VERSION 5.7 ;
  NOWIREEXTENSIONATPIN ON ;
  DIVIDERCHAR "/" ;
  BUSBITCHARS "[]" ;
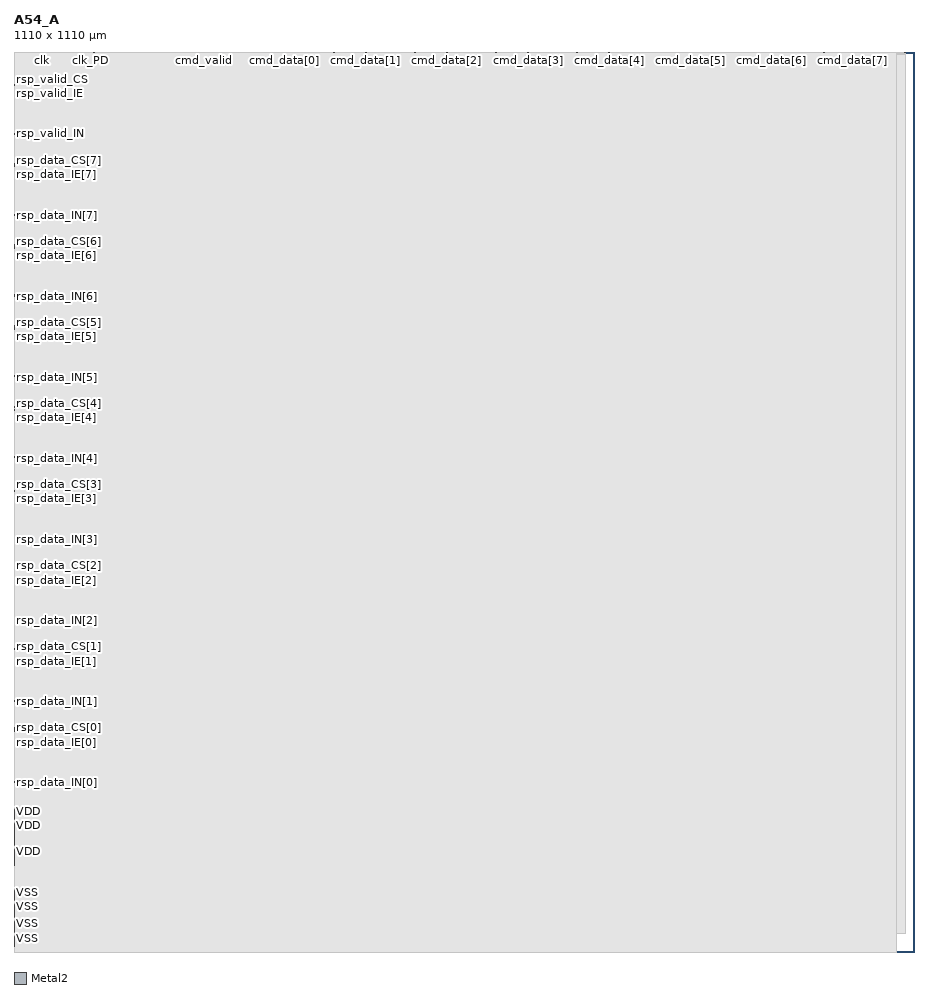
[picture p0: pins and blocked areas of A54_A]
MACRO A54_A
  CLASS BLOCK ;
  FOREIGN A54_A ;
  ORIGIN 0.000 0.000 ;
  SIZE 1110.000 BY 1110.000 ;
  PIN VDD
    DIRECTION INOUT ;
    USE POWER ;
    PORT
      LAYER Metal2 ;
        RECT 0.000 106.360 1.000 178.640 ;
    END
  END VDD
  PIN VDD
    DIRECTION INOUT ;
    USE POWER ;
    PORT
      LAYER Metal2 ;
        RECT 0.000 118.760 1.000 129.010 ;
    END
  END VDD
  PIN VDD
    DIRECTION INOUT ;
    USE POWER ;
    PORT
      LAYER Metal2 ;
        RECT 0.000 130.610 1.000 140.860 ;
    END
  END VDD
  PIN VDD
    DIRECTION INOUT ;
    USE POWER ;
    PORT
      LAYER Metal2 ;
        RECT 0.000 144.140 1.000 154.390 ;
    END
  END VDD
  PIN VDD
    DIRECTION INOUT ;
    USE POWER ;
    PORT
      LAYER Metal2 ;
        RECT 0.000 155.990 1.000 166.240 ;
    END
  END VDD
  PIN VDD
    DIRECTION INOUT ;
    USE POWER ;
    PORT
      LAYER Metal2 ;
        RECT 0.000 169.140 1.000 178.640 ;
    END
  END VDD
  PIN VSS
    DIRECTION INOUT ;
    USE GROUND ;
    PORT
      LAYER Metal2 ;
        RECT 0.000 6.360 1.000 78.640 ;
    END
  END VSS
  PIN VSS
    DIRECTION INOUT ;
    USE GROUND ;
    PORT
      LAYER Metal2 ;
        RECT 0.000 18.760 1.000 29.010 ;
    END
  END VSS
  PIN VSS
    DIRECTION INOUT ;
    USE GROUND ;
    PORT
      LAYER Metal2 ;
        RECT 0.000 30.610 1.000 40.860 ;
    END
  END VSS
  PIN VSS
    DIRECTION INOUT ;
    USE GROUND ;
    PORT
      LAYER Metal2 ;
        RECT 0.000 44.140 1.000 54.390 ;
    END
  END VSS
  PIN VSS
    DIRECTION INOUT ;
    USE GROUND ;
    PORT
      LAYER Metal2 ;
        RECT 0.000 55.990 1.000 66.240 ;
    END
  END VSS
  PIN VSS
    DIRECTION INOUT ;
    USE GROUND ;
    PORT
      LAYER Metal2 ;
        RECT 0.000 69.140 1.000 78.640 ;
    END
  END VSS
  PIN clk
    DIRECTION INPUT ;
    USE SIGNAL ;
    ANTENNAGATEAREA 4.738000 ;
    ANTENNADIFFAREA 0.410400 ;
    PORT
      LAYER Metal2 ;
        RECT 33.760 1109.000 34.140 1110.000 ;
    END
  END clk
  PIN clk_PD
    DIRECTION OUTPUT ;
    USE SIGNAL ;
    ANTENNADIFFAREA 0.360800 ;
    PORT
      LAYER Metal2 ;
        RECT 94.290 1109.000 94.670 1110.000 ;
    END
  END clk_PD
  PIN clk_PU
    DIRECTION OUTPUT ;
    USE SIGNAL ;
    ANTENNADIFFAREA 0.360800 ;
    PORT
      LAYER Metal2 ;
        RECT 98.655 1109.000 99.035 1110.000 ;
    END
  END clk_PU
  PIN cmd_data[0]
    DIRECTION INPUT ;
    USE SIGNAL ;
    ANTENNAGATEAREA 1.102000 ;
    ANTENNADIFFAREA 0.410400 ;
    PORT
      LAYER Metal2 ;
        RECT 333.760 1109.000 334.140 1110.000 ;
    END
  END cmd_data[0]
  PIN cmd_data[1]
    DIRECTION INPUT ;
    USE SIGNAL ;
    ANTENNAGATEAREA 1.102000 ;
    ANTENNADIFFAREA 0.410400 ;
    PORT
      LAYER Metal2 ;
        RECT 433.760 1109.000 434.140 1110.000 ;
    END
  END cmd_data[1]
  PIN cmd_data[2]
    DIRECTION INPUT ;
    USE SIGNAL ;
    ANTENNAGATEAREA 0.396000 ;
    ANTENNADIFFAREA 0.410400 ;
    PORT
      LAYER Metal2 ;
        RECT 533.760 1109.000 534.140 1110.000 ;
    END
  END cmd_data[2]
  PIN cmd_data[3]
    DIRECTION INPUT ;
    USE SIGNAL ;
    ANTENNAGATEAREA 0.396000 ;
    ANTENNADIFFAREA 0.410400 ;
    PORT
      LAYER Metal2 ;
        RECT 633.760 1109.000 634.140 1110.000 ;
    END
  END cmd_data[3]
  PIN cmd_data[4]
    DIRECTION INPUT ;
    USE SIGNAL ;
    ANTENNAGATEAREA 0.396000 ;
    ANTENNADIFFAREA 0.410400 ;
    PORT
      LAYER Metal2 ;
        RECT 733.760 1109.000 734.140 1110.000 ;
    END
  END cmd_data[4]
  PIN cmd_data[5]
    DIRECTION INPUT ;
    USE SIGNAL ;
    ANTENNAGATEAREA 0.396000 ;
    ANTENNADIFFAREA 0.410400 ;
    PORT
      LAYER Metal2 ;
        RECT 833.760 1109.000 834.140 1110.000 ;
    END
  END cmd_data[5]
  PIN cmd_data[6]
    DIRECTION INPUT ;
    USE SIGNAL ;
    ANTENNAGATEAREA 0.396000 ;
    ANTENNADIFFAREA 0.410400 ;
    PORT
      LAYER Metal2 ;
        RECT 933.760 1109.000 934.140 1110.000 ;
    END
  END cmd_data[6]
  PIN cmd_data[7]
    DIRECTION INPUT ;
    USE SIGNAL ;
    ANTENNAGATEAREA 0.396000 ;
    ANTENNADIFFAREA 0.410400 ;
    PORT
      LAYER Metal2 ;
        RECT 1033.760 1109.000 1034.140 1110.000 ;
    END
  END cmd_data[7]
  PIN cmd_data_PD[0]
    DIRECTION OUTPUT ;
    USE SIGNAL ;
    ANTENNADIFFAREA 0.360800 ;
    PORT
      LAYER Metal2 ;
        RECT 394.290 1109.000 394.670 1110.000 ;
    END
  END cmd_data_PD[0]
  PIN cmd_data_PD[1]
    DIRECTION OUTPUT ;
    USE SIGNAL ;
    ANTENNADIFFAREA 0.360800 ;
    PORT
      LAYER Metal2 ;
        RECT 494.290 1109.000 494.670 1110.000 ;
    END
  END cmd_data_PD[1]
  PIN cmd_data_PD[2]
    DIRECTION OUTPUT ;
    USE SIGNAL ;
    ANTENNADIFFAREA 0.360800 ;
    PORT
      LAYER Metal2 ;
        RECT 594.290 1109.000 594.670 1110.000 ;
    END
  END cmd_data_PD[2]
  PIN cmd_data_PD[3]
    DIRECTION OUTPUT ;
    USE SIGNAL ;
    ANTENNADIFFAREA 0.360800 ;
    PORT
      LAYER Metal2 ;
        RECT 694.290 1109.000 694.670 1110.000 ;
    END
  END cmd_data_PD[3]
  PIN cmd_data_PD[4]
    DIRECTION OUTPUT ;
    USE SIGNAL ;
    ANTENNADIFFAREA 0.360800 ;
    PORT
      LAYER Metal2 ;
        RECT 794.290 1109.000 794.670 1110.000 ;
    END
  END cmd_data_PD[4]
  PIN cmd_data_PD[5]
    DIRECTION OUTPUT ;
    USE SIGNAL ;
    ANTENNADIFFAREA 0.360800 ;
    PORT
      LAYER Metal2 ;
        RECT 894.290 1109.000 894.670 1110.000 ;
    END
  END cmd_data_PD[5]
  PIN cmd_data_PD[6]
    DIRECTION OUTPUT ;
    USE SIGNAL ;
    ANTENNADIFFAREA 0.360800 ;
    PORT
      LAYER Metal2 ;
        RECT 994.290 1109.000 994.670 1110.000 ;
    END
  END cmd_data_PD[6]
  PIN cmd_data_PD[7]
    DIRECTION OUTPUT ;
    USE SIGNAL ;
    ANTENNADIFFAREA 0.360800 ;
    PORT
      LAYER Metal2 ;
        RECT 1094.290 1109.000 1094.670 1110.000 ;
    END
  END cmd_data_PD[7]
  PIN cmd_data_PU[0]
    DIRECTION OUTPUT ;
    USE SIGNAL ;
    ANTENNADIFFAREA 0.360800 ;
    PORT
      LAYER Metal2 ;
        RECT 398.655 1109.000 399.035 1110.000 ;
    END
  END cmd_data_PU[0]
  PIN cmd_data_PU[1]
    DIRECTION OUTPUT ;
    USE SIGNAL ;
    ANTENNADIFFAREA 0.360800 ;
    PORT
      LAYER Metal2 ;
        RECT 498.655 1109.000 499.035 1110.000 ;
    END
  END cmd_data_PU[1]
  PIN cmd_data_PU[2]
    DIRECTION OUTPUT ;
    USE SIGNAL ;
    ANTENNADIFFAREA 0.360800 ;
    PORT
      LAYER Metal2 ;
        RECT 598.655 1109.000 599.035 1110.000 ;
    END
  END cmd_data_PU[2]
  PIN cmd_data_PU[3]
    DIRECTION OUTPUT ;
    USE SIGNAL ;
    ANTENNADIFFAREA 0.360800 ;
    PORT
      LAYER Metal2 ;
        RECT 698.655 1109.000 699.035 1110.000 ;
    END
  END cmd_data_PU[3]
  PIN cmd_data_PU[4]
    DIRECTION OUTPUT ;
    USE SIGNAL ;
    ANTENNADIFFAREA 0.360800 ;
    PORT
      LAYER Metal2 ;
        RECT 798.655 1109.000 799.035 1110.000 ;
    END
  END cmd_data_PU[4]
  PIN cmd_data_PU[5]
    DIRECTION OUTPUT ;
    USE SIGNAL ;
    ANTENNADIFFAREA 0.360800 ;
    PORT
      LAYER Metal2 ;
        RECT 898.655 1109.000 899.035 1110.000 ;
    END
  END cmd_data_PU[5]
  PIN cmd_data_PU[6]
    DIRECTION OUTPUT ;
    USE SIGNAL ;
    ANTENNADIFFAREA 0.360800 ;
    PORT
      LAYER Metal2 ;
        RECT 998.655 1109.000 999.035 1110.000 ;
    END
  END cmd_data_PU[6]
  PIN cmd_data_PU[7]
    DIRECTION OUTPUT ;
    USE SIGNAL ;
    ANTENNADIFFAREA 0.360800 ;
    PORT
      LAYER Metal2 ;
        RECT 1098.655 1109.000 1099.035 1110.000 ;
    END
  END cmd_data_PU[7]
  PIN cmd_valid
    DIRECTION INPUT ;
    USE SIGNAL ;
    ANTENNAGATEAREA 0.396000 ;
    ANTENNADIFFAREA 0.410400 ;
    PORT
      LAYER Metal2 ;
        RECT 233.760 1109.000 234.140 1110.000 ;
    END
  END cmd_valid
  PIN cmd_valid_PD
    DIRECTION OUTPUT ;
    USE SIGNAL ;
    ANTENNADIFFAREA 0.360800 ;
    PORT
      LAYER Metal2 ;
        RECT 294.290 1109.000 294.670 1110.000 ;
    END
  END cmd_valid_PD
  PIN cmd_valid_PU
    DIRECTION OUTPUT ;
    USE SIGNAL ;
    ANTENNADIFFAREA 0.360800 ;
    PORT
      LAYER Metal2 ;
        RECT 298.655 1109.000 299.035 1110.000 ;
    END
  END cmd_valid_PU
  PIN rsp_data_CS[0]
    DIRECTION OUTPUT ;
    USE SIGNAL ;
    ANTENNADIFFAREA 0.360800 ;
    PORT
      LAYER Metal2 ;
        RECT 0.000 276.260 1.000 276.640 ;
    END
  END rsp_data_CS[0]
  PIN rsp_data_CS[1]
    DIRECTION OUTPUT ;
    USE SIGNAL ;
    ANTENNADIFFAREA 0.360800 ;
    PORT
      LAYER Metal2 ;
        RECT 0.000 376.260 1.000 376.640 ;
    END
  END rsp_data_CS[1]
  PIN rsp_data_CS[2]
    DIRECTION OUTPUT ;
    USE SIGNAL ;
    ANTENNADIFFAREA 0.360800 ;
    PORT
      LAYER Metal2 ;
        RECT 0.000 476.260 1.000 476.640 ;
    END
  END rsp_data_CS[2]
  PIN rsp_data_CS[3]
    DIRECTION OUTPUT ;
    USE SIGNAL ;
    ANTENNADIFFAREA 0.360800 ;
    PORT
      LAYER Metal2 ;
        RECT 0.000 576.260 1.000 576.640 ;
    END
  END rsp_data_CS[3]
  PIN rsp_data_CS[4]
    DIRECTION OUTPUT ;
    USE SIGNAL ;
    ANTENNADIFFAREA 0.360800 ;
    PORT
      LAYER Metal2 ;
        RECT 0.000 676.260 1.000 676.640 ;
    END
  END rsp_data_CS[4]
  PIN rsp_data_CS[5]
    DIRECTION OUTPUT ;
    USE SIGNAL ;
    ANTENNADIFFAREA 0.360800 ;
    PORT
      LAYER Metal2 ;
        RECT 0.000 776.260 1.000 776.640 ;
    END
  END rsp_data_CS[5]
  PIN rsp_data_CS[6]
    DIRECTION OUTPUT ;
    USE SIGNAL ;
    ANTENNADIFFAREA 0.360800 ;
    PORT
      LAYER Metal2 ;
        RECT 0.000 876.260 1.000 876.640 ;
    END
  END rsp_data_CS[6]
  PIN rsp_data_CS[7]
    DIRECTION OUTPUT ;
    USE SIGNAL ;
    ANTENNADIFFAREA 0.360800 ;
    PORT
      LAYER Metal2 ;
        RECT 0.000 976.260 1.000 976.640 ;
    END
  END rsp_data_CS[7]
  PIN rsp_data_IE[0]
    DIRECTION OUTPUT ;
    USE SIGNAL ;
    ANTENNADIFFAREA 0.360800 ;
    PORT
      LAYER Metal2 ;
        RECT 0.000 268.235 1.000 268.615 ;
    END
  END rsp_data_IE[0]
  PIN rsp_data_IE[1]
    DIRECTION OUTPUT ;
    USE SIGNAL ;
    ANTENNADIFFAREA 0.360800 ;
    PORT
      LAYER Metal2 ;
        RECT 0.000 368.235 1.000 368.615 ;
    END
  END rsp_data_IE[1]
  PIN rsp_data_IE[2]
    DIRECTION OUTPUT ;
    USE SIGNAL ;
    ANTENNADIFFAREA 0.360800 ;
    PORT
      LAYER Metal2 ;
        RECT 0.000 468.235 1.000 468.615 ;
    END
  END rsp_data_IE[2]
  PIN rsp_data_IE[3]
    DIRECTION OUTPUT ;
    USE SIGNAL ;
    ANTENNADIFFAREA 0.360800 ;
    PORT
      LAYER Metal2 ;
        RECT 0.000 568.235 1.000 568.615 ;
    END
  END rsp_data_IE[3]
  PIN rsp_data_IE[4]
    DIRECTION OUTPUT ;
    USE SIGNAL ;
    ANTENNADIFFAREA 0.360800 ;
    PORT
      LAYER Metal2 ;
        RECT 0.000 668.235 1.000 668.615 ;
    END
  END rsp_data_IE[4]
  PIN rsp_data_IE[5]
    DIRECTION OUTPUT ;
    USE SIGNAL ;
    ANTENNADIFFAREA 0.360800 ;
    PORT
      LAYER Metal2 ;
        RECT 0.000 768.235 1.000 768.615 ;
    END
  END rsp_data_IE[5]
  PIN rsp_data_IE[6]
    DIRECTION OUTPUT ;
    USE SIGNAL ;
    ANTENNADIFFAREA 0.360800 ;
    PORT
      LAYER Metal2 ;
        RECT 0.000 868.235 1.000 868.615 ;
    END
  END rsp_data_IE[6]
  PIN rsp_data_IE[7]
    DIRECTION OUTPUT ;
    USE SIGNAL ;
    ANTENNADIFFAREA 0.360800 ;
    PORT
      LAYER Metal2 ;
        RECT 0.000 968.235 1.000 968.615 ;
    END
  END rsp_data_IE[7]
  PIN rsp_data_IN[0]
    DIRECTION INPUT ;
    USE SIGNAL ;
    PORT
      LAYER Metal2 ;
        RECT 0.000 208.760 1.000 209.140 ;
    END
  END rsp_data_IN[0]
  PIN rsp_data_IN[1]
    DIRECTION INPUT ;
    USE SIGNAL ;
    PORT
      LAYER Metal2 ;
        RECT 0.000 308.760 1.000 309.140 ;
    END
  END rsp_data_IN[1]
  PIN rsp_data_IN[2]
    DIRECTION INPUT ;
    USE SIGNAL ;
    PORT
      LAYER Metal2 ;
        RECT 0.000 408.760 1.000 409.140 ;
    END
  END rsp_data_IN[2]
  PIN rsp_data_IN[3]
    DIRECTION INPUT ;
    USE SIGNAL ;
    PORT
      LAYER Metal2 ;
        RECT 0.000 508.760 1.000 509.140 ;
    END
  END rsp_data_IN[3]
  PIN rsp_data_IN[4]
    DIRECTION INPUT ;
    USE SIGNAL ;
    PORT
      LAYER Metal2 ;
        RECT 0.000 608.760 1.000 609.140 ;
    END
  END rsp_data_IN[4]
  PIN rsp_data_IN[5]
    DIRECTION INPUT ;
    USE SIGNAL ;
    PORT
      LAYER Metal2 ;
        RECT 0.000 708.760 1.000 709.140 ;
    END
  END rsp_data_IN[5]
  PIN rsp_data_IN[6]
    DIRECTION INPUT ;
    USE SIGNAL ;
    PORT
      LAYER Metal2 ;
        RECT 0.000 808.760 1.000 809.140 ;
    END
  END rsp_data_IN[6]
  PIN rsp_data_IN[7]
    DIRECTION INPUT ;
    USE SIGNAL ;
    PORT
      LAYER Metal2 ;
        RECT 0.000 908.760 1.000 909.140 ;
    END
  END rsp_data_IN[7]
  PIN rsp_data_OE[0]
    DIRECTION OUTPUT ;
    USE SIGNAL ;
    ANTENNADIFFAREA 0.536800 ;
    PORT
      LAYER Metal2 ;
        RECT 0.000 209.490 1.000 209.870 ;
    END
  END rsp_data_OE[0]
  PIN rsp_data_OE[1]
    DIRECTION OUTPUT ;
    USE SIGNAL ;
    ANTENNADIFFAREA 0.536800 ;
    PORT
      LAYER Metal2 ;
        RECT 0.000 309.490 1.000 309.870 ;
    END
  END rsp_data_OE[1]
  PIN rsp_data_OE[2]
    DIRECTION OUTPUT ;
    USE SIGNAL ;
    ANTENNADIFFAREA 0.536800 ;
    PORT
      LAYER Metal2 ;
        RECT 0.000 409.490 1.000 409.870 ;
    END
  END rsp_data_OE[2]
  PIN rsp_data_OE[3]
    DIRECTION OUTPUT ;
    USE SIGNAL ;
    ANTENNADIFFAREA 0.536800 ;
    PORT
      LAYER Metal2 ;
        RECT 0.000 509.490 1.000 509.870 ;
    END
  END rsp_data_OE[3]
  PIN rsp_data_OE[4]
    DIRECTION OUTPUT ;
    USE SIGNAL ;
    ANTENNADIFFAREA 0.536800 ;
    PORT
      LAYER Metal2 ;
        RECT 0.000 609.490 1.000 609.870 ;
    END
  END rsp_data_OE[4]
  PIN rsp_data_OE[5]
    DIRECTION OUTPUT ;
    USE SIGNAL ;
    ANTENNADIFFAREA 0.536800 ;
    PORT
      LAYER Metal2 ;
        RECT 0.000 709.490 1.000 709.870 ;
    END
  END rsp_data_OE[5]
  PIN rsp_data_OE[6]
    DIRECTION OUTPUT ;
    USE SIGNAL ;
    ANTENNADIFFAREA 0.536800 ;
    PORT
      LAYER Metal2 ;
        RECT 0.000 809.490 1.000 809.870 ;
    END
  END rsp_data_OE[6]
  PIN rsp_data_OE[7]
    DIRECTION OUTPUT ;
    USE SIGNAL ;
    ANTENNADIFFAREA 0.536800 ;
    PORT
      LAYER Metal2 ;
        RECT 0.000 909.490 1.000 909.870 ;
    END
  END rsp_data_OE[7]
  PIN rsp_data_OUT[0]
    DIRECTION OUTPUT ;
    USE SIGNAL ;
    ANTENNADIFFAREA 0.897600 ;
    PORT
      LAYER Metal2 ;
        RECT 0.000 210.220 1.000 210.600 ;
    END
  END rsp_data_OUT[0]
  PIN rsp_data_OUT[1]
    DIRECTION OUTPUT ;
    USE SIGNAL ;
    ANTENNADIFFAREA 0.897600 ;
    PORT
      LAYER Metal2 ;
        RECT 0.000 310.220 1.000 310.600 ;
    END
  END rsp_data_OUT[1]
  PIN rsp_data_OUT[2]
    DIRECTION OUTPUT ;
    USE SIGNAL ;
    ANTENNADIFFAREA 0.897600 ;
    PORT
      LAYER Metal2 ;
        RECT 0.000 410.220 1.000 410.600 ;
    END
  END rsp_data_OUT[2]
  PIN rsp_data_OUT[3]
    DIRECTION OUTPUT ;
    USE SIGNAL ;
    ANTENNADIFFAREA 0.897600 ;
    PORT
      LAYER Metal2 ;
        RECT 0.000 510.220 1.000 510.600 ;
    END
  END rsp_data_OUT[3]
  PIN rsp_data_OUT[4]
    DIRECTION OUTPUT ;
    USE SIGNAL ;
    ANTENNADIFFAREA 0.897600 ;
    PORT
      LAYER Metal2 ;
        RECT 0.000 610.220 1.000 610.600 ;
    END
  END rsp_data_OUT[4]
  PIN rsp_data_OUT[5]
    DIRECTION OUTPUT ;
    USE SIGNAL ;
    ANTENNADIFFAREA 0.897600 ;
    PORT
      LAYER Metal2 ;
        RECT 0.000 710.220 1.000 710.600 ;
    END
  END rsp_data_OUT[5]
  PIN rsp_data_OUT[6]
    DIRECTION OUTPUT ;
    USE SIGNAL ;
    ANTENNADIFFAREA 0.897600 ;
    PORT
      LAYER Metal2 ;
        RECT 0.000 810.220 1.000 810.600 ;
    END
  END rsp_data_OUT[6]
  PIN rsp_data_OUT[7]
    DIRECTION OUTPUT ;
    USE SIGNAL ;
    ANTENNADIFFAREA 0.897600 ;
    PORT
      LAYER Metal2 ;
        RECT 0.000 910.220 1.000 910.600 ;
    END
  END rsp_data_OUT[7]
  PIN rsp_data_PDRV0[0]
    DIRECTION OUTPUT ;
    USE SIGNAL ;
    ANTENNADIFFAREA 0.360800 ;
    PORT
      LAYER Metal2 ;
        RECT 0.000 272.510 1.000 272.890 ;
    END
  END rsp_data_PDRV0[0]
  PIN rsp_data_PDRV0[1]
    DIRECTION OUTPUT ;
    USE SIGNAL ;
    ANTENNADIFFAREA 0.360800 ;
    PORT
      LAYER Metal2 ;
        RECT 0.000 372.510 1.000 372.890 ;
    END
  END rsp_data_PDRV0[1]
  PIN rsp_data_PDRV0[2]
    DIRECTION OUTPUT ;
    USE SIGNAL ;
    ANTENNADIFFAREA 0.360800 ;
    PORT
      LAYER Metal2 ;
        RECT 0.000 472.510 1.000 472.890 ;
    END
  END rsp_data_PDRV0[2]
  PIN rsp_data_PDRV0[3]
    DIRECTION OUTPUT ;
    USE SIGNAL ;
    ANTENNADIFFAREA 0.360800 ;
    PORT
      LAYER Metal2 ;
        RECT 0.000 572.510 1.000 572.890 ;
    END
  END rsp_data_PDRV0[3]
  PIN rsp_data_PDRV0[4]
    DIRECTION OUTPUT ;
    USE SIGNAL ;
    ANTENNADIFFAREA 0.360800 ;
    PORT
      LAYER Metal2 ;
        RECT 0.000 672.510 1.000 672.890 ;
    END
  END rsp_data_PDRV0[4]
  PIN rsp_data_PDRV0[5]
    DIRECTION OUTPUT ;
    USE SIGNAL ;
    ANTENNADIFFAREA 0.360800 ;
    PORT
      LAYER Metal2 ;
        RECT 0.000 772.510 1.000 772.890 ;
    END
  END rsp_data_PDRV0[5]
  PIN rsp_data_PDRV0[6]
    DIRECTION OUTPUT ;
    USE SIGNAL ;
    ANTENNADIFFAREA 0.360800 ;
    PORT
      LAYER Metal2 ;
        RECT 0.000 872.510 1.000 872.890 ;
    END
  END rsp_data_PDRV0[6]
  PIN rsp_data_PDRV0[7]
    DIRECTION OUTPUT ;
    USE SIGNAL ;
    ANTENNADIFFAREA 0.360800 ;
    PORT
      LAYER Metal2 ;
        RECT 0.000 972.510 1.000 972.890 ;
    END
  END rsp_data_PDRV0[7]
  PIN rsp_data_PDRV1[0]
    DIRECTION OUTPUT ;
    USE SIGNAL ;
    ANTENNADIFFAREA 0.360800 ;
    PORT
      LAYER Metal2 ;
        RECT 0.000 271.800 1.000 272.180 ;
    END
  END rsp_data_PDRV1[0]
  PIN rsp_data_PDRV1[1]
    DIRECTION OUTPUT ;
    USE SIGNAL ;
    ANTENNADIFFAREA 0.360800 ;
    PORT
      LAYER Metal2 ;
        RECT 0.000 371.800 1.000 372.180 ;
    END
  END rsp_data_PDRV1[1]
  PIN rsp_data_PDRV1[2]
    DIRECTION OUTPUT ;
    USE SIGNAL ;
    ANTENNADIFFAREA 0.360800 ;
    PORT
      LAYER Metal2 ;
        RECT 0.000 471.800 1.000 472.180 ;
    END
  END rsp_data_PDRV1[2]
  PIN rsp_data_PDRV1[3]
    DIRECTION OUTPUT ;
    USE SIGNAL ;
    ANTENNADIFFAREA 0.360800 ;
    PORT
      LAYER Metal2 ;
        RECT 0.000 571.800 1.000 572.180 ;
    END
  END rsp_data_PDRV1[3]
  PIN rsp_data_PDRV1[4]
    DIRECTION OUTPUT ;
    USE SIGNAL ;
    ANTENNADIFFAREA 0.360800 ;
    PORT
      LAYER Metal2 ;
        RECT 0.000 671.800 1.000 672.180 ;
    END
  END rsp_data_PDRV1[4]
  PIN rsp_data_PDRV1[5]
    DIRECTION OUTPUT ;
    USE SIGNAL ;
    ANTENNADIFFAREA 0.360800 ;
    PORT
      LAYER Metal2 ;
        RECT 0.000 771.800 1.000 772.180 ;
    END
  END rsp_data_PDRV1[5]
  PIN rsp_data_PDRV1[6]
    DIRECTION OUTPUT ;
    USE SIGNAL ;
    ANTENNADIFFAREA 0.360800 ;
    PORT
      LAYER Metal2 ;
        RECT 0.000 871.800 1.000 872.180 ;
    END
  END rsp_data_PDRV1[6]
  PIN rsp_data_PDRV1[7]
    DIRECTION OUTPUT ;
    USE SIGNAL ;
    ANTENNADIFFAREA 0.360800 ;
    PORT
      LAYER Metal2 ;
        RECT 0.000 971.800 1.000 972.180 ;
    END
  END rsp_data_PDRV1[7]
  PIN rsp_data_PD[0]
    DIRECTION OUTPUT ;
    USE SIGNAL ;
    ANTENNADIFFAREA 0.360800 ;
    PORT
      LAYER Metal2 ;
        RECT 0.000 269.290 1.000 269.670 ;
    END
  END rsp_data_PD[0]
  PIN rsp_data_PD[1]
    DIRECTION OUTPUT ;
    USE SIGNAL ;
    ANTENNADIFFAREA 0.360800 ;
    PORT
      LAYER Metal2 ;
        RECT 0.000 369.290 1.000 369.670 ;
    END
  END rsp_data_PD[1]
  PIN rsp_data_PD[2]
    DIRECTION OUTPUT ;
    USE SIGNAL ;
    ANTENNADIFFAREA 0.360800 ;
    PORT
      LAYER Metal2 ;
        RECT 0.000 469.290 1.000 469.670 ;
    END
  END rsp_data_PD[2]
  PIN rsp_data_PD[3]
    DIRECTION OUTPUT ;
    USE SIGNAL ;
    ANTENNADIFFAREA 0.360800 ;
    PORT
      LAYER Metal2 ;
        RECT 0.000 569.290 1.000 569.670 ;
    END
  END rsp_data_PD[3]
  PIN rsp_data_PD[4]
    DIRECTION OUTPUT ;
    USE SIGNAL ;
    ANTENNADIFFAREA 0.360800 ;
    PORT
      LAYER Metal2 ;
        RECT 0.000 669.290 1.000 669.670 ;
    END
  END rsp_data_PD[4]
  PIN rsp_data_PD[5]
    DIRECTION OUTPUT ;
    USE SIGNAL ;
    ANTENNADIFFAREA 0.360800 ;
    PORT
      LAYER Metal2 ;
        RECT 0.000 769.290 1.000 769.670 ;
    END
  END rsp_data_PD[5]
  PIN rsp_data_PD[6]
    DIRECTION OUTPUT ;
    USE SIGNAL ;
    ANTENNADIFFAREA 0.360800 ;
    PORT
      LAYER Metal2 ;
        RECT 0.000 869.290 1.000 869.670 ;
    END
  END rsp_data_PD[6]
  PIN rsp_data_PD[7]
    DIRECTION OUTPUT ;
    USE SIGNAL ;
    ANTENNADIFFAREA 0.360800 ;
    PORT
      LAYER Metal2 ;
        RECT 0.000 969.290 1.000 969.670 ;
    END
  END rsp_data_PD[7]
  PIN rsp_data_PU[0]
    DIRECTION OUTPUT ;
    USE SIGNAL ;
    ANTENNADIFFAREA 0.360800 ;
    PORT
      LAYER Metal2 ;
        RECT 0.000 273.655 1.000 274.035 ;
    END
  END rsp_data_PU[0]
  PIN rsp_data_PU[1]
    DIRECTION OUTPUT ;
    USE SIGNAL ;
    ANTENNADIFFAREA 0.360800 ;
    PORT
      LAYER Metal2 ;
        RECT 0.000 373.655 1.000 374.035 ;
    END
  END rsp_data_PU[1]
  PIN rsp_data_PU[2]
    DIRECTION OUTPUT ;
    USE SIGNAL ;
    ANTENNADIFFAREA 0.360800 ;
    PORT
      LAYER Metal2 ;
        RECT 0.000 473.655 1.000 474.035 ;
    END
  END rsp_data_PU[2]
  PIN rsp_data_PU[3]
    DIRECTION OUTPUT ;
    USE SIGNAL ;
    ANTENNADIFFAREA 0.360800 ;
    PORT
      LAYER Metal2 ;
        RECT 0.000 573.655 1.000 574.035 ;
    END
  END rsp_data_PU[3]
  PIN rsp_data_PU[4]
    DIRECTION OUTPUT ;
    USE SIGNAL ;
    ANTENNADIFFAREA 0.360800 ;
    PORT
      LAYER Metal2 ;
        RECT 0.000 673.655 1.000 674.035 ;
    END
  END rsp_data_PU[4]
  PIN rsp_data_PU[5]
    DIRECTION OUTPUT ;
    USE SIGNAL ;
    ANTENNADIFFAREA 0.360800 ;
    PORT
      LAYER Metal2 ;
        RECT 0.000 773.655 1.000 774.035 ;
    END
  END rsp_data_PU[5]
  PIN rsp_data_PU[6]
    DIRECTION OUTPUT ;
    USE SIGNAL ;
    ANTENNADIFFAREA 0.360800 ;
    PORT
      LAYER Metal2 ;
        RECT 0.000 873.655 1.000 874.035 ;
    END
  END rsp_data_PU[6]
  PIN rsp_data_PU[7]
    DIRECTION OUTPUT ;
    USE SIGNAL ;
    ANTENNADIFFAREA 0.360800 ;
    PORT
      LAYER Metal2 ;
        RECT 0.000 973.655 1.000 974.035 ;
    END
  END rsp_data_PU[7]
  PIN rsp_data_SL[0]
    DIRECTION OUTPUT ;
    USE SIGNAL ;
    ANTENNADIFFAREA 0.360800 ;
    PORT
      LAYER Metal2 ;
        RECT 0.000 210.950 1.000 211.330 ;
    END
  END rsp_data_SL[0]
  PIN rsp_data_SL[1]
    DIRECTION OUTPUT ;
    USE SIGNAL ;
    ANTENNADIFFAREA 0.360800 ;
    PORT
      LAYER Metal2 ;
        RECT 0.000 310.950 1.000 311.330 ;
    END
  END rsp_data_SL[1]
  PIN rsp_data_SL[2]
    DIRECTION OUTPUT ;
    USE SIGNAL ;
    ANTENNADIFFAREA 0.360800 ;
    PORT
      LAYER Metal2 ;
        RECT 0.000 410.950 1.000 411.330 ;
    END
  END rsp_data_SL[2]
  PIN rsp_data_SL[3]
    DIRECTION OUTPUT ;
    USE SIGNAL ;
    ANTENNADIFFAREA 0.360800 ;
    PORT
      LAYER Metal2 ;
        RECT 0.000 510.950 1.000 511.330 ;
    END
  END rsp_data_SL[3]
  PIN rsp_data_SL[4]
    DIRECTION OUTPUT ;
    USE SIGNAL ;
    ANTENNADIFFAREA 0.360800 ;
    PORT
      LAYER Metal2 ;
        RECT 0.000 610.950 1.000 611.330 ;
    END
  END rsp_data_SL[4]
  PIN rsp_data_SL[5]
    DIRECTION OUTPUT ;
    USE SIGNAL ;
    ANTENNADIFFAREA 0.360800 ;
    PORT
      LAYER Metal2 ;
        RECT 0.000 710.950 1.000 711.330 ;
    END
  END rsp_data_SL[5]
  PIN rsp_data_SL[6]
    DIRECTION OUTPUT ;
    USE SIGNAL ;
    ANTENNADIFFAREA 0.360800 ;
    PORT
      LAYER Metal2 ;
        RECT 0.000 810.950 1.000 811.330 ;
    END
  END rsp_data_SL[6]
  PIN rsp_data_SL[7]
    DIRECTION OUTPUT ;
    USE SIGNAL ;
    ANTENNADIFFAREA 0.360800 ;
    PORT
      LAYER Metal2 ;
        RECT 0.000 910.950 1.000 911.330 ;
    END
  END rsp_data_SL[7]
  PIN rsp_valid_CS
    DIRECTION OUTPUT ;
    USE SIGNAL ;
    ANTENNADIFFAREA 0.360800 ;
    PORT
      LAYER Metal2 ;
        RECT 0.000 1076.260 1.000 1076.640 ;
    END
  END rsp_valid_CS
  PIN rsp_valid_IE
    DIRECTION OUTPUT ;
    USE SIGNAL ;
    ANTENNADIFFAREA 0.360800 ;
    PORT
      LAYER Metal2 ;
        RECT 0.000 1068.235 1.000 1068.615 ;
    END
  END rsp_valid_IE
  PIN rsp_valid_IN
    DIRECTION INPUT ;
    USE SIGNAL ;
    PORT
      LAYER Metal2 ;
        RECT 0.000 1008.760 1.000 1009.140 ;
    END
  END rsp_valid_IN
  PIN rsp_valid_OE
    DIRECTION OUTPUT ;
    USE SIGNAL ;
    ANTENNADIFFAREA 0.536800 ;
    PORT
      LAYER Metal2 ;
        RECT 0.000 1009.490 1.000 1009.870 ;
    END
  END rsp_valid_OE
  PIN rsp_valid_OUT
    DIRECTION OUTPUT ;
    USE SIGNAL ;
    ANTENNADIFFAREA 0.897600 ;
    PORT
      LAYER Metal2 ;
        RECT 0.000 1010.220 1.000 1010.600 ;
    END
  END rsp_valid_OUT
  PIN rsp_valid_PD
    DIRECTION OUTPUT ;
    USE SIGNAL ;
    ANTENNADIFFAREA 0.360800 ;
    PORT
      LAYER Metal2 ;
        RECT 0.000 1069.290 1.000 1069.670 ;
    END
  END rsp_valid_PD
  PIN rsp_valid_PDRV0
    DIRECTION OUTPUT ;
    USE SIGNAL ;
    ANTENNADIFFAREA 0.360800 ;
    PORT
      LAYER Metal2 ;
        RECT 0.000 1072.510 1.000 1072.890 ;
    END
  END rsp_valid_PDRV0
  PIN rsp_valid_PDRV1
    DIRECTION OUTPUT ;
    USE SIGNAL ;
    ANTENNADIFFAREA 0.360800 ;
    PORT
      LAYER Metal2 ;
        RECT 0.000 1071.800 1.000 1072.180 ;
    END
  END rsp_valid_PDRV1
  PIN rsp_valid_PU
    DIRECTION OUTPUT ;
    USE SIGNAL ;
    ANTENNADIFFAREA 0.360800 ;
    PORT
      LAYER Metal2 ;
        RECT 0.000 1073.655 1.000 1074.035 ;
    END
  END rsp_valid_PU
  PIN rsp_valid_SL
    DIRECTION OUTPUT ;
    USE SIGNAL ;
    ANTENNADIFFAREA 0.360800 ;
    PORT
      LAYER Metal2 ;
        RECT 0.000 1010.950 1.000 1011.330 ;
    END
  END rsp_valid_SL
  PIN rst_n
    DIRECTION INPUT ;
    USE SIGNAL ;
    ANTENNAGATEAREA 6.612000 ;
    ANTENNADIFFAREA 0.410400 ;
    PORT
      LAYER Metal2 ;
        RECT 133.760 1109.000 134.140 1110.000 ;
    END
  END rst_n
  PIN rst_n_PD
    DIRECTION OUTPUT ;
    USE SIGNAL ;
    ANTENNADIFFAREA 0.360800 ;
    PORT
      LAYER Metal2 ;
        RECT 194.290 1109.000 194.670 1110.000 ;
    END
  END rst_n_PD
  PIN rst_n_PU
    DIRECTION OUTPUT ;
    USE SIGNAL ;
    ANTENNADIFFAREA 0.360800 ;
    PORT
      LAYER Metal2 ;
        RECT 198.655 1109.000 199.035 1110.000 ;
    END
  END rst_n_PU
  OBS
      LAYER Nwell ;
        RECT 19.730 23.090 1090.190 1090.190 ;
      LAYER Metal1 ;
        RECT 20.160 23.220 1089.760 1090.060 ;
      LAYER Metal2 ;
        RECT 0.140 1108.700 33.460 1109.220 ;
        RECT 34.440 1108.700 93.990 1109.220 ;
        RECT 94.970 1108.700 98.355 1109.220 ;
        RECT 99.335 1108.700 133.460 1109.220 ;
        RECT 134.440 1108.700 193.990 1109.220 ;
        RECT 194.970 1108.700 198.355 1109.220 ;
        RECT 199.335 1108.700 233.460 1109.220 ;
        RECT 234.440 1108.700 293.990 1109.220 ;
        RECT 294.970 1108.700 298.355 1109.220 ;
        RECT 299.335 1108.700 333.460 1109.220 ;
        RECT 334.440 1108.700 393.990 1109.220 ;
        RECT 394.970 1108.700 398.355 1109.220 ;
        RECT 399.335 1108.700 433.460 1109.220 ;
        RECT 434.440 1108.700 493.990 1109.220 ;
        RECT 494.970 1108.700 498.355 1109.220 ;
        RECT 499.335 1108.700 533.460 1109.220 ;
        RECT 534.440 1108.700 593.990 1109.220 ;
        RECT 594.970 1108.700 598.355 1109.220 ;
        RECT 599.335 1108.700 633.460 1109.220 ;
        RECT 634.440 1108.700 693.990 1109.220 ;
        RECT 694.970 1108.700 698.355 1109.220 ;
        RECT 699.335 1108.700 733.460 1109.220 ;
        RECT 734.440 1108.700 793.990 1109.220 ;
        RECT 794.970 1108.700 798.355 1109.220 ;
        RECT 799.335 1108.700 833.460 1109.220 ;
        RECT 834.440 1108.700 893.990 1109.220 ;
        RECT 894.970 1108.700 898.355 1109.220 ;
        RECT 899.335 1108.700 933.460 1109.220 ;
        RECT 934.440 1108.700 993.990 1109.220 ;
        RECT 994.970 1108.700 998.355 1109.220 ;
        RECT 999.335 1108.700 1033.460 1109.220 ;
        RECT 1034.440 1108.700 1093.990 1109.220 ;
        RECT 1094.970 1108.700 1098.355 1109.220 ;
        RECT 0.140 1076.940 1098.985 1108.700 ;
        RECT 1.300 1075.960 1098.985 1076.940 ;
        RECT 0.140 1074.335 1098.985 1075.960 ;
        RECT 1.300 1073.355 1098.985 1074.335 ;
        RECT 0.140 1073.190 1098.985 1073.355 ;
        RECT 1.300 1071.500 1098.985 1073.190 ;
        RECT 0.140 1069.970 1098.985 1071.500 ;
        RECT 1.300 1068.990 1098.985 1069.970 ;
        RECT 0.140 1068.915 1098.985 1068.990 ;
        RECT 1.300 1067.935 1098.985 1068.915 ;
        RECT 0.140 1011.630 1098.985 1067.935 ;
        RECT 1.300 1008.460 1098.985 1011.630 ;
        RECT 0.140 976.940 1098.985 1008.460 ;
        RECT 1.300 975.960 1098.985 976.940 ;
        RECT 0.140 974.335 1098.985 975.960 ;
        RECT 1.300 973.355 1098.985 974.335 ;
        RECT 0.140 973.190 1098.985 973.355 ;
        RECT 1.300 971.500 1098.985 973.190 ;
        RECT 0.140 969.970 1098.985 971.500 ;
        RECT 1.300 968.990 1098.985 969.970 ;
        RECT 0.140 968.915 1098.985 968.990 ;
        RECT 1.300 967.935 1098.985 968.915 ;
        RECT 0.140 911.630 1098.985 967.935 ;
        RECT 1.300 908.460 1098.985 911.630 ;
        RECT 0.140 876.940 1098.985 908.460 ;
        RECT 1.300 875.960 1098.985 876.940 ;
        RECT 0.140 874.335 1098.985 875.960 ;
        RECT 1.300 873.355 1098.985 874.335 ;
        RECT 0.140 873.190 1098.985 873.355 ;
        RECT 1.300 871.500 1098.985 873.190 ;
        RECT 0.140 869.970 1098.985 871.500 ;
        RECT 1.300 868.990 1098.985 869.970 ;
        RECT 0.140 868.915 1098.985 868.990 ;
        RECT 1.300 867.935 1098.985 868.915 ;
        RECT 0.140 811.630 1098.985 867.935 ;
        RECT 1.300 808.460 1098.985 811.630 ;
        RECT 0.140 776.940 1098.985 808.460 ;
        RECT 1.300 775.960 1098.985 776.940 ;
        RECT 0.140 774.335 1098.985 775.960 ;
        RECT 1.300 773.355 1098.985 774.335 ;
        RECT 0.140 773.190 1098.985 773.355 ;
        RECT 1.300 771.500 1098.985 773.190 ;
        RECT 0.140 769.970 1098.985 771.500 ;
        RECT 1.300 768.990 1098.985 769.970 ;
        RECT 0.140 768.915 1098.985 768.990 ;
        RECT 1.300 767.935 1098.985 768.915 ;
        RECT 0.140 711.630 1098.985 767.935 ;
        RECT 1.300 708.460 1098.985 711.630 ;
        RECT 0.140 676.940 1098.985 708.460 ;
        RECT 1.300 675.960 1098.985 676.940 ;
        RECT 0.140 674.335 1098.985 675.960 ;
        RECT 1.300 673.355 1098.985 674.335 ;
        RECT 0.140 673.190 1098.985 673.355 ;
        RECT 1.300 671.500 1098.985 673.190 ;
        RECT 0.140 669.970 1098.985 671.500 ;
        RECT 1.300 668.990 1098.985 669.970 ;
        RECT 0.140 668.915 1098.985 668.990 ;
        RECT 1.300 667.935 1098.985 668.915 ;
        RECT 0.140 611.630 1098.985 667.935 ;
        RECT 1.300 608.460 1098.985 611.630 ;
        RECT 0.140 576.940 1098.985 608.460 ;
        RECT 1.300 575.960 1098.985 576.940 ;
        RECT 0.140 574.335 1098.985 575.960 ;
        RECT 1.300 573.355 1098.985 574.335 ;
        RECT 0.140 573.190 1098.985 573.355 ;
        RECT 1.300 571.500 1098.985 573.190 ;
        RECT 0.140 569.970 1098.985 571.500 ;
        RECT 1.300 568.990 1098.985 569.970 ;
        RECT 0.140 568.915 1098.985 568.990 ;
        RECT 1.300 567.935 1098.985 568.915 ;
        RECT 0.140 511.630 1098.985 567.935 ;
        RECT 1.300 508.460 1098.985 511.630 ;
        RECT 0.140 476.940 1098.985 508.460 ;
        RECT 1.300 475.960 1098.985 476.940 ;
        RECT 0.140 474.335 1098.985 475.960 ;
        RECT 1.300 473.355 1098.985 474.335 ;
        RECT 0.140 473.190 1098.985 473.355 ;
        RECT 1.300 471.500 1098.985 473.190 ;
        RECT 0.140 469.970 1098.985 471.500 ;
        RECT 1.300 468.990 1098.985 469.970 ;
        RECT 0.140 468.915 1098.985 468.990 ;
        RECT 1.300 467.935 1098.985 468.915 ;
        RECT 0.140 411.630 1098.985 467.935 ;
        RECT 1.300 408.460 1098.985 411.630 ;
        RECT 0.140 376.940 1098.985 408.460 ;
        RECT 1.300 375.960 1098.985 376.940 ;
        RECT 0.140 374.335 1098.985 375.960 ;
        RECT 1.300 373.355 1098.985 374.335 ;
        RECT 0.140 373.190 1098.985 373.355 ;
        RECT 1.300 371.500 1098.985 373.190 ;
        RECT 0.140 369.970 1098.985 371.500 ;
        RECT 1.300 368.990 1098.985 369.970 ;
        RECT 0.140 368.915 1098.985 368.990 ;
        RECT 1.300 367.935 1098.985 368.915 ;
        RECT 0.140 311.630 1098.985 367.935 ;
        RECT 1.300 308.460 1098.985 311.630 ;
        RECT 0.140 276.940 1098.985 308.460 ;
        RECT 1.300 275.960 1098.985 276.940 ;
        RECT 0.140 274.335 1098.985 275.960 ;
        RECT 1.300 273.355 1098.985 274.335 ;
        RECT 0.140 273.190 1098.985 273.355 ;
        RECT 1.300 271.500 1098.985 273.190 ;
        RECT 0.140 269.970 1098.985 271.500 ;
        RECT 1.300 268.990 1098.985 269.970 ;
        RECT 0.140 268.915 1098.985 268.990 ;
        RECT 1.300 267.935 1098.985 268.915 ;
        RECT 0.140 211.630 1098.985 267.935 ;
        RECT 1.300 208.460 1098.985 211.630 ;
        RECT 0.140 178.940 1098.985 208.460 ;
        RECT 1.300 106.060 1098.985 178.940 ;
        RECT 0.140 78.940 1098.985 106.060 ;
        RECT 1.300 22.520 1098.985 78.940 ;
      LAYER Metal3 ;
        RECT 0.090 23.380 1099.035 1106.420 ;
      LAYER Metal4 ;
        RECT 0.140 0.000 1088.980 1110.000 ;
  END
END A54_A
END LIBRARY

